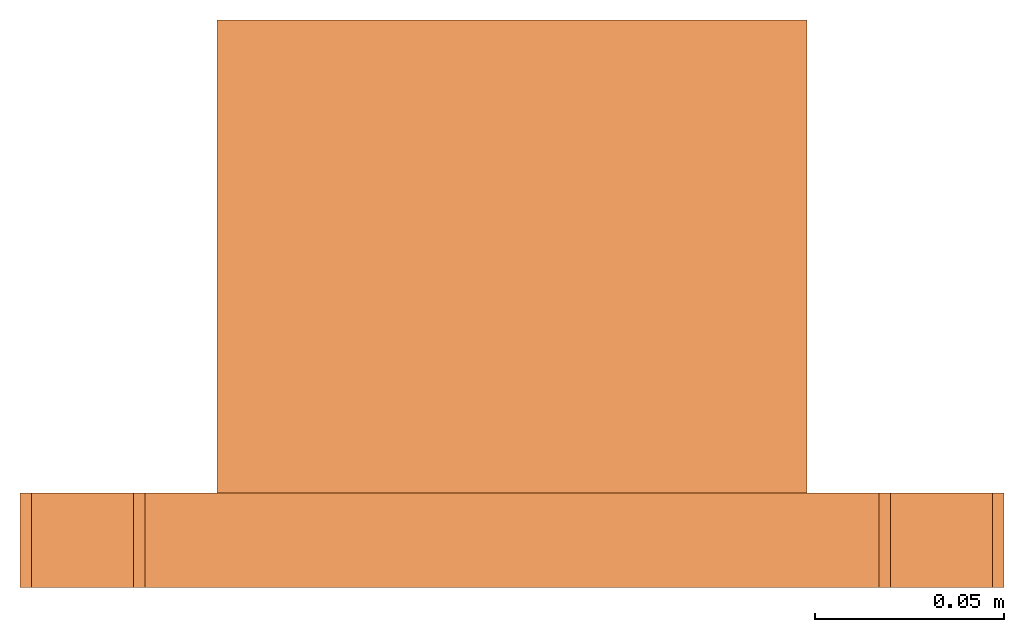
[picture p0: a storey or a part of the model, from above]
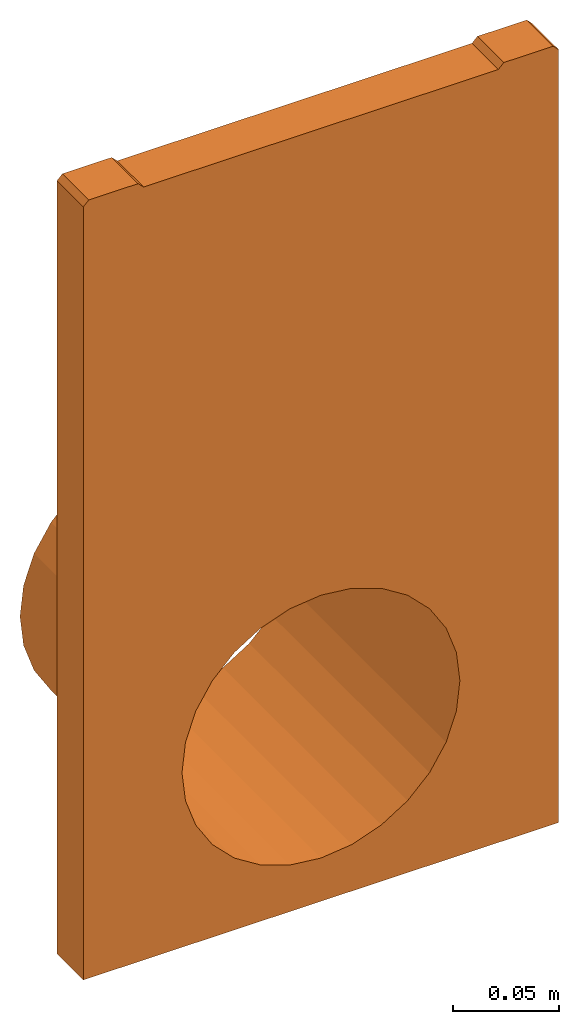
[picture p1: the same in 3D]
Properties of the parts of a building model (IFC2X3)

# File
Description: ViewDefinition [CoordinationView]
File name: 33208 - PD200 F 208 Inlet outlet endcap.ifc
Time: 2013-10-11T12:57:44
Written by: Autodesk Revit 2013
Made in: 20120221_2030(x64)

# IfcProject, Project Number
LongName: Project Name; Phase: Project Status

# IfcSite, Default
RefLatitude: 42, 21, 30, 344238; RefLongitude: -71, -3, -35, -194702; RefElevation: 0 mm

# IfcBuilding
Pset_BuildingCommon - NumberOfStoreys: 2
Other - Project Name: Project Name; Project Status: Project Status; Project Number: Project Number; Project Address: Enter address here; Client Name: Owner; Project Issue Date: Issue Date

# IfcBuildingStorey (2)
Constraints - Elevation Base: 0
Graphics - Symbol: M_Level Head - Circle: M_Level Head - Circle; Symbol at End 2 Default: yes; Symbol at End 1 Default: no; Color: 0; Line Pattern: Center; Line Weight: 1
Identity Data - Structural: no; Building Story: yes
Dimensions - Computation Height: 0 mm
Name | LongName = Name | Elevation (mm) = Constraints, Elevation (mm)
B.O. Footing | B.O. Footing | -4600
T.O. Footing | T.O. Footing | -4300

# IfcBuildingElementProxy: 33208 - PD200 F 208 Inlet/outlet endcap, Civil-Drainage-Channel-ACO-RoadDrain 200:33208 - PD200 F 208 Inlet/outlet endcap:33208 - PD200 F 208 Inlet/outlet endcap:309971
In: B.O. Footing
Material: Phenolic Resin, Acetal Resin, Black
Other - Revision: 1; CreatedBy: www.aco.co.uk
Green Building Properties - Channel Recyclable: N/A; End Cap Recycled Material Content: 20% minimum; End Cap Recyclable: Fully recyclable; Access Cover/Frame Recycled Material Content: N/A; Access Cover/Frame Recyclable: N/A; Channel Recycled Material Content: N/A
Materials and Finishes - Channel Colour: N/A; End Cap Colour: Black; Channel Material: N/A; Connection Pipe Material: PVCu; Connection Pipe Colour: Brown; Grating Material: N/A; Grating Finish: N/A; Access Cover/Frame Material: N/A; Grating Colour: N/A; Access Cover/Frame Colour: N/A; End Cap Material: Vienite® Synthetic Resin Concrete; Access Cover/Frame Finish: N/A
Constraints - Level: Level: T.O. Footing; Moves With Nearby Elements: no
Dimensions - Custom Void Length: 0 mm; Volume: 2577322 mm3; Straight Void Length: 25 mm; Length: 500 mm; Pipe Depth: 349 mm; Void Depth: -450 mm; I/O End Cap Void: 228 mm; Total Depth: 450 mm; Invert Depth.: 275 mm; Straight Void Start: 0 mm
Phasing - Phase Created: Phase 1
Pset_BuildingElementProxyCommon - Reference: 33208 - PD200 F 208 Inlet/outlet endcap
Data - Product Weight: 4.7 Kg; ACO Hydraulic Design Software: N/A; Product Standard: N/A; Hydraulic Performance: N/A; Channel C.S.A: N/A; Product Dimensions: 25mm x 260mm x 450mm (LxWxH); Load Class: N/A; Invert Depth: N/A; Installation - Concrete Grade: N/A; Concrete Surround Volume - Load Class F 900 - Concrete Pavement: N/A; Connection Pipe O.D: Ø160mm
Identity Data - Watermark 2: This file is water marked and users are prohibited to reproduce, adapt, distribute this information; Manufacturer: ACO Technologies plc - ACO Water Management Division; Maintenance guidelines: http://www.aco.co.uk/download.php?id=256; OmniClass Title: Rainwater Removal; Cost: 0; Product Code: 33208; Assembly Description: Rain Water Drainage; Product Page URL: http://www.aco.co.uk/product_detail.php?id=21; Fax: +44 (0)1462 815895; URL: www.aco.co.uk; Type Comments: ACO RoadDrain PD200 F 208 Inlet/Outlet End Cap; Installation guidelines: http://www.aco.co.uk/download.php?id=256; Watermark 1: This file is the property of ACO Technologies PLC; Product brochure: http://www.aco.co.uk/download.php?id=256; Model: ACO RoadDrain 200 PD200F; Model Description: Monolithic Channel drainage system; OmniClass Number: 23.70.50.24; e-mail Technical: technical@aco.co.uk; Watermarked By: www.aco.co.uk; Telephone: +44 (0)1462 816666; Watermarked With: BIM Manager Premium Suite; Address: ACO Business Park, Hitchin Road, Shefford, Bedfordshire, United Kingdom SG17 5TE; Assembly Code: D2040; Price: POA - contact ACO; e-mail Sales: customersupport@aco.co.uk
General - TagNumber: 0.000000; SerialNumber: 0.000000
Construction - Channel 260mm Wide: no; Inlet Outlet end cap: yes; Access unit: no; Closing End Cap: no

# IfcOpeningElement: Recess
In: T.O. Footing
Dimensions - Area: 26010000 mm2; Perimeter: 20400 mm; Volume: 40310186426 mm3; Thickness: 1550 mm
Constraints - Level: Level: T.O. Footing; Room Bounding: yes; Height Offset From Level: 0 mm; Related to Mass: no
Structural - Enable Analytical Model: no; Structural: no
Phasing - Phase Created: Phase 1
Analytical Properties - Thermal mass: 2039700; Roughness: 1; Thermal Resistance (R): 1.79211; Absorptance: 0.1; Heat Transfer Coefficient (U): 0.558
Construction - Function: 0; Default Thickness: 1550 mm
Materials and Finishes - Structural Material: Grass
Graphics - Coarse Scale Fill Color: 0

# IfcSlab: Floor:Generic Floor - 400mm, Floor:Generic Floor - 400mm:136436
In: T.O. Footing
PredefinedType: FLOOR; Material: Grass 50 mm, Earth 1500 mm
Dimensions - Area: 26010000 mm2; Perimeter: 20400 mm; Volume: 40310186426 mm3; Thickness: 1550 mm
Constraints - Level: Level: T.O. Footing; Room Bounding: yes; Height Offset From Level: 0 mm; Related to Mass: no
Structural - Enable Analytical Model: no; Structural: no
Phasing - Phase Created: Phase 1
Pset_SlabCommon - Reference: Generic Floor - 400mm; IsExternal: no; LoadBearing: yes
Analytical Properties - Thermal mass: 2039700; Roughness: 1; Thermal Resistance (R): 1.79211; Absorptance: 0.1; Heat Transfer Coefficient (U): 0.558
Construction - Function: 0; Default Thickness: 1550 mm
Materials and Finishes - Structural Material: Grass
Graphics - Coarse Scale Fill Color: 0
